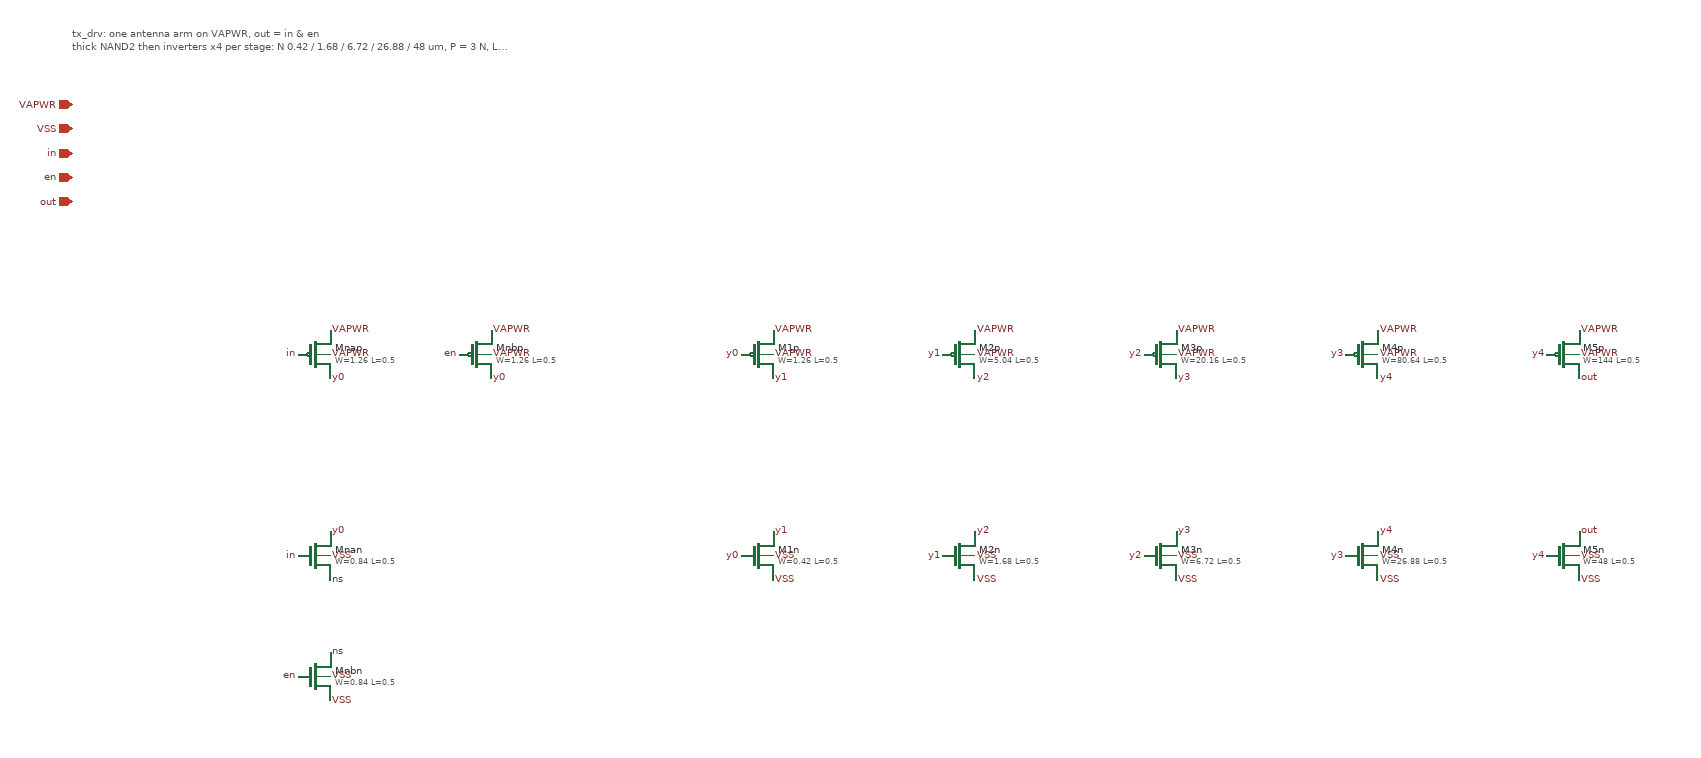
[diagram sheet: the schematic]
v {xschem version=3.4.5 file_version=1.2
}
G {}
K {}
V {}
S {}
E {}
T {tx_drv: one antenna arm on VAPWR, out = in & en
thick NAND2 then inverters x4 per stage: N 0.42 / 1.68 / 6.72 / 26.88 / 48 um, P = 3 N, L 0.5} -700 -560 0 0 0.4 0.4 {}
C {devices/iopin.sym} -700 -460 0 0 {name=p1
lab=VAPWR}
C {devices/iopin.sym} -700 -430 0 0 {name=p2
lab=VSS}
C {devices/iopin.sym} -700 -400 0 0 {name=p3
lab=in}
C {devices/iopin.sym} -700 -370 0 0 {name=p4
lab=en}
C {devices/iopin.sym} -700 -340 0 0 {name=p5
lab=out}
C {sky130_fd_pr/pfet_g5v0d10v5.sym} -400 -150 0 0 {name=Mnap
nf=1
mult=1
ad="'int((nf+1)/2) * W/nf * 0.29'"
pd="'2*int((nf+1)/2) * (W/nf + 0.29)'"
as="'int((nf+2)/2) * W/nf * 0.29'"
ps="'2*int((nf+2)/2) * (W/nf + 0.29)'"
nrd="'0.29 / W'"
nrs="'0.29 / W'"
sa=0
sb=0
sd=0
L=0.5
W=1.26
model=pfet_g5v0d10v5
spiceprefix=X}
C {devices/lab_pin.sym} -380 -120 0 1 {name=p6
sig_type=std_logic
lab=y0}
C {devices/lab_pin.sym} -420 -150 0 0 {name=p7
sig_type=std_logic
lab=in}
C {devices/lab_pin.sym} -380 -180 0 1 {name=p8
sig_type=std_logic
lab=VAPWR}
C {devices/lab_pin.sym} -380 -150 0 1 {name=p9
sig_type=std_logic
lab=VAPWR}
C {sky130_fd_pr/pfet_g5v0d10v5.sym} -200 -150 0 0 {name=Mnbp
nf=1
mult=1
ad="'int((nf+1)/2) * W/nf * 0.29'"
pd="'2*int((nf+1)/2) * (W/nf + 0.29)'"
as="'int((nf+2)/2) * W/nf * 0.29'"
ps="'2*int((nf+2)/2) * (W/nf + 0.29)'"
nrd="'0.29 / W'"
nrs="'0.29 / W'"
sa=0
sb=0
sd=0
L=0.5
W=1.26
model=pfet_g5v0d10v5
spiceprefix=X}
C {devices/lab_pin.sym} -180 -120 0 1 {name=p10
sig_type=std_logic
lab=y0}
C {devices/lab_pin.sym} -220 -150 0 0 {name=p11
sig_type=std_logic
lab=en}
C {devices/lab_pin.sym} -180 -180 0 1 {name=p12
sig_type=std_logic
lab=VAPWR}
C {devices/lab_pin.sym} -180 -150 0 1 {name=p13
sig_type=std_logic
lab=VAPWR}
C {sky130_fd_pr/nfet_g5v0d10v5.sym} -400 100 0 0 {name=Mnan
nf=1
mult=1
ad="'int((nf+1)/2) * W/nf * 0.29'"
pd="'2*int((nf+1)/2) * (W/nf + 0.29)'"
as="'int((nf+2)/2) * W/nf * 0.29'"
ps="'2*int((nf+2)/2) * (W/nf + 0.29)'"
nrd="'0.29 / W'"
nrs="'0.29 / W'"
sa=0
sb=0
sd=0
L=0.5
W=0.84
model=nfet_g5v0d10v5
spiceprefix=X}
C {devices/lab_pin.sym} -380 70 0 1 {name=p14
sig_type=std_logic
lab=y0}
C {devices/lab_pin.sym} -420 100 0 0 {name=p15
sig_type=std_logic
lab=in}
C {devices/lab_pin.sym} -380 130 0 1 {name=p16
sig_type=std_logic
lab=ns}
C {devices/lab_pin.sym} -380 100 0 1 {name=p17
sig_type=std_logic
lab=VSS}
C {sky130_fd_pr/nfet_g5v0d10v5.sym} -400 250 0 0 {name=Mnbn
nf=1
mult=1
ad="'int((nf+1)/2) * W/nf * 0.29'"
pd="'2*int((nf+1)/2) * (W/nf + 0.29)'"
as="'int((nf+2)/2) * W/nf * 0.29'"
ps="'2*int((nf+2)/2) * (W/nf + 0.29)'"
nrd="'0.29 / W'"
nrs="'0.29 / W'"
sa=0
sb=0
sd=0
L=0.5
W=0.84
model=nfet_g5v0d10v5
spiceprefix=X}
C {devices/lab_pin.sym} -380 220 0 1 {name=p18
sig_type=std_logic
lab=ns}
C {devices/lab_pin.sym} -420 250 0 0 {name=p19
sig_type=std_logic
lab=en}
C {devices/lab_pin.sym} -380 280 0 1 {name=p20
sig_type=std_logic
lab=VSS}
C {devices/lab_pin.sym} -380 250 0 1 {name=p21
sig_type=std_logic
lab=VSS}
C {sky130_fd_pr/pfet_g5v0d10v5.sym} 150 -150 0 0 {name=M1p
nf=1
mult=1
ad="'int((nf+1)/2) * W/nf * 0.29'"
pd="'2*int((nf+1)/2) * (W/nf + 0.29)'"
as="'int((nf+2)/2) * W/nf * 0.29'"
ps="'2*int((nf+2)/2) * (W/nf + 0.29)'"
nrd="'0.29 / W'"
nrs="'0.29 / W'"
sa=0
sb=0
sd=0
L=0.5
W=1.26
model=pfet_g5v0d10v5
spiceprefix=X}
C {devices/lab_pin.sym} 170 -120 0 1 {name=p22
sig_type=std_logic
lab=y1}
C {devices/lab_pin.sym} 130 -150 0 0 {name=p23
sig_type=std_logic
lab=y0}
C {devices/lab_pin.sym} 170 -180 0 1 {name=p24
sig_type=std_logic
lab=VAPWR}
C {devices/lab_pin.sym} 170 -150 0 1 {name=p25
sig_type=std_logic
lab=VAPWR}
C {sky130_fd_pr/nfet_g5v0d10v5.sym} 150 100 0 0 {name=M1n
nf=1
mult=1
ad="'int((nf+1)/2) * W/nf * 0.29'"
pd="'2*int((nf+1)/2) * (W/nf + 0.29)'"
as="'int((nf+2)/2) * W/nf * 0.29'"
ps="'2*int((nf+2)/2) * (W/nf + 0.29)'"
nrd="'0.29 / W'"
nrs="'0.29 / W'"
sa=0
sb=0
sd=0
L=0.5
W=0.42
model=nfet_g5v0d10v5
spiceprefix=X}
C {devices/lab_pin.sym} 170 70 0 1 {name=p26
sig_type=std_logic
lab=y1}
C {devices/lab_pin.sym} 130 100 0 0 {name=p27
sig_type=std_logic
lab=y0}
C {devices/lab_pin.sym} 170 130 0 1 {name=p28
sig_type=std_logic
lab=VSS}
C {devices/lab_pin.sym} 170 100 0 1 {name=p29
sig_type=std_logic
lab=VSS}
C {sky130_fd_pr/pfet_g5v0d10v5.sym} 400 -150 0 0 {name=M2p
nf=1
mult=1
ad="'int((nf+1)/2) * W/nf * 0.29'"
pd="'2*int((nf+1)/2) * (W/nf + 0.29)'"
as="'int((nf+2)/2) * W/nf * 0.29'"
ps="'2*int((nf+2)/2) * (W/nf + 0.29)'"
nrd="'0.29 / W'"
nrs="'0.29 / W'"
sa=0
sb=0
sd=0
L=0.5
W=5.04
model=pfet_g5v0d10v5
spiceprefix=X}
C {devices/lab_pin.sym} 420 -120 0 1 {name=p30
sig_type=std_logic
lab=y2}
C {devices/lab_pin.sym} 380 -150 0 0 {name=p31
sig_type=std_logic
lab=y1}
C {devices/lab_pin.sym} 420 -180 0 1 {name=p32
sig_type=std_logic
lab=VAPWR}
C {devices/lab_pin.sym} 420 -150 0 1 {name=p33
sig_type=std_logic
lab=VAPWR}
C {sky130_fd_pr/nfet_g5v0d10v5.sym} 400 100 0 0 {name=M2n
nf=1
mult=1
ad="'int((nf+1)/2) * W/nf * 0.29'"
pd="'2*int((nf+1)/2) * (W/nf + 0.29)'"
as="'int((nf+2)/2) * W/nf * 0.29'"
ps="'2*int((nf+2)/2) * (W/nf + 0.29)'"
nrd="'0.29 / W'"
nrs="'0.29 / W'"
sa=0
sb=0
sd=0
L=0.5
W=1.68
model=nfet_g5v0d10v5
spiceprefix=X}
C {devices/lab_pin.sym} 420 70 0 1 {name=p34
sig_type=std_logic
lab=y2}
C {devices/lab_pin.sym} 380 100 0 0 {name=p35
sig_type=std_logic
lab=y1}
C {devices/lab_pin.sym} 420 130 0 1 {name=p36
sig_type=std_logic
lab=VSS}
C {devices/lab_pin.sym} 420 100 0 1 {name=p37
sig_type=std_logic
lab=VSS}
C {sky130_fd_pr/pfet_g5v0d10v5.sym} 650 -150 0 0 {name=M3p
nf=2
mult=1
ad="'int((nf+1)/2) * W/nf * 0.29'"
pd="'2*int((nf+1)/2) * (W/nf + 0.29)'"
as="'int((nf+2)/2) * W/nf * 0.29'"
ps="'2*int((nf+2)/2) * (W/nf + 0.29)'"
nrd="'0.29 / W'"
nrs="'0.29 / W'"
sa=0
sb=0
sd=0
L=0.5
W=20.16
model=pfet_g5v0d10v5
spiceprefix=X}
C {devices/lab_pin.sym} 670 -120 0 1 {name=p38
sig_type=std_logic
lab=y3}
C {devices/lab_pin.sym} 630 -150 0 0 {name=p39
sig_type=std_logic
lab=y2}
C {devices/lab_pin.sym} 670 -180 0 1 {name=p40
sig_type=std_logic
lab=VAPWR}
C {devices/lab_pin.sym} 670 -150 0 1 {name=p41
sig_type=std_logic
lab=VAPWR}
C {sky130_fd_pr/nfet_g5v0d10v5.sym} 650 100 0 0 {name=M3n
nf=1
mult=1
ad="'int((nf+1)/2) * W/nf * 0.29'"
pd="'2*int((nf+1)/2) * (W/nf + 0.29)'"
as="'int((nf+2)/2) * W/nf * 0.29'"
ps="'2*int((nf+2)/2) * (W/nf + 0.29)'"
nrd="'0.29 / W'"
nrs="'0.29 / W'"
sa=0
sb=0
sd=0
L=0.5
W=6.72
model=nfet_g5v0d10v5
spiceprefix=X}
C {devices/lab_pin.sym} 670 70 0 1 {name=p42
sig_type=std_logic
lab=y3}
C {devices/lab_pin.sym} 630 100 0 0 {name=p43
sig_type=std_logic
lab=y2}
C {devices/lab_pin.sym} 670 130 0 1 {name=p44
sig_type=std_logic
lab=VSS}
C {devices/lab_pin.sym} 670 100 0 1 {name=p45
sig_type=std_logic
lab=VSS}
C {sky130_fd_pr/pfet_g5v0d10v5.sym} 900 -150 0 0 {name=M4p
nf=8
mult=1
ad="'int((nf+1)/2) * W/nf * 0.29'"
pd="'2*int((nf+1)/2) * (W/nf + 0.29)'"
as="'int((nf+2)/2) * W/nf * 0.29'"
ps="'2*int((nf+2)/2) * (W/nf + 0.29)'"
nrd="'0.29 / W'"
nrs="'0.29 / W'"
sa=0
sb=0
sd=0
L=0.5
W=80.64
model=pfet_g5v0d10v5
spiceprefix=X}
C {devices/lab_pin.sym} 920 -120 0 1 {name=p46
sig_type=std_logic
lab=y4}
C {devices/lab_pin.sym} 880 -150 0 0 {name=p47
sig_type=std_logic
lab=y3}
C {devices/lab_pin.sym} 920 -180 0 1 {name=p48
sig_type=std_logic
lab=VAPWR}
C {devices/lab_pin.sym} 920 -150 0 1 {name=p49
sig_type=std_logic
lab=VAPWR}
C {sky130_fd_pr/nfet_g5v0d10v5.sym} 900 100 0 0 {name=M4n
nf=3
mult=1
ad="'int((nf+1)/2) * W/nf * 0.29'"
pd="'2*int((nf+1)/2) * (W/nf + 0.29)'"
as="'int((nf+2)/2) * W/nf * 0.29'"
ps="'2*int((nf+2)/2) * (W/nf + 0.29)'"
nrd="'0.29 / W'"
nrs="'0.29 / W'"
sa=0
sb=0
sd=0
L=0.5
W=26.88
model=nfet_g5v0d10v5
spiceprefix=X}
C {devices/lab_pin.sym} 920 70 0 1 {name=p50
sig_type=std_logic
lab=y4}
C {devices/lab_pin.sym} 880 100 0 0 {name=p51
sig_type=std_logic
lab=y3}
C {devices/lab_pin.sym} 920 130 0 1 {name=p52
sig_type=std_logic
lab=VSS}
C {devices/lab_pin.sym} 920 100 0 1 {name=p53
sig_type=std_logic
lab=VSS}
C {sky130_fd_pr/pfet_g5v0d10v5.sym} 1150 -150 0 0 {name=M5p
nf=14
mult=1
ad="'int((nf+1)/2) * W/nf * 0.29'"
pd="'2*int((nf+1)/2) * (W/nf + 0.29)'"
as="'int((nf+2)/2) * W/nf * 0.29'"
ps="'2*int((nf+2)/2) * (W/nf + 0.29)'"
nrd="'0.29 / W'"
nrs="'0.29 / W'"
sa=0
sb=0
sd=0
L=0.5
W=144
model=pfet_g5v0d10v5
spiceprefix=X}
C {devices/lab_pin.sym} 1170 -120 0 1 {name=p54
sig_type=std_logic
lab=out}
C {devices/lab_pin.sym} 1130 -150 0 0 {name=p55
sig_type=std_logic
lab=y4}
C {devices/lab_pin.sym} 1170 -180 0 1 {name=p56
sig_type=std_logic
lab=VAPWR}
C {devices/lab_pin.sym} 1170 -150 0 1 {name=p57
sig_type=std_logic
lab=VAPWR}
C {sky130_fd_pr/nfet_g5v0d10v5.sym} 1150 100 0 0 {name=M5n
nf=5
mult=1
ad="'int((nf+1)/2) * W/nf * 0.29'"
pd="'2*int((nf+1)/2) * (W/nf + 0.29)'"
as="'int((nf+2)/2) * W/nf * 0.29'"
ps="'2*int((nf+2)/2) * (W/nf + 0.29)'"
nrd="'0.29 / W'"
nrs="'0.29 / W'"
sa=0
sb=0
sd=0
L=0.5
W=48
model=nfet_g5v0d10v5
spiceprefix=X}
C {devices/lab_pin.sym} 1170 70 0 1 {name=p58
sig_type=std_logic
lab=out}
C {devices/lab_pin.sym} 1130 100 0 0 {name=p59
sig_type=std_logic
lab=y4}
C {devices/lab_pin.sym} 1170 130 0 1 {name=p60
sig_type=std_logic
lab=VSS}
C {devices/lab_pin.sym} 1170 100 0 1 {name=p61
sig_type=std_logic
lab=VSS}
